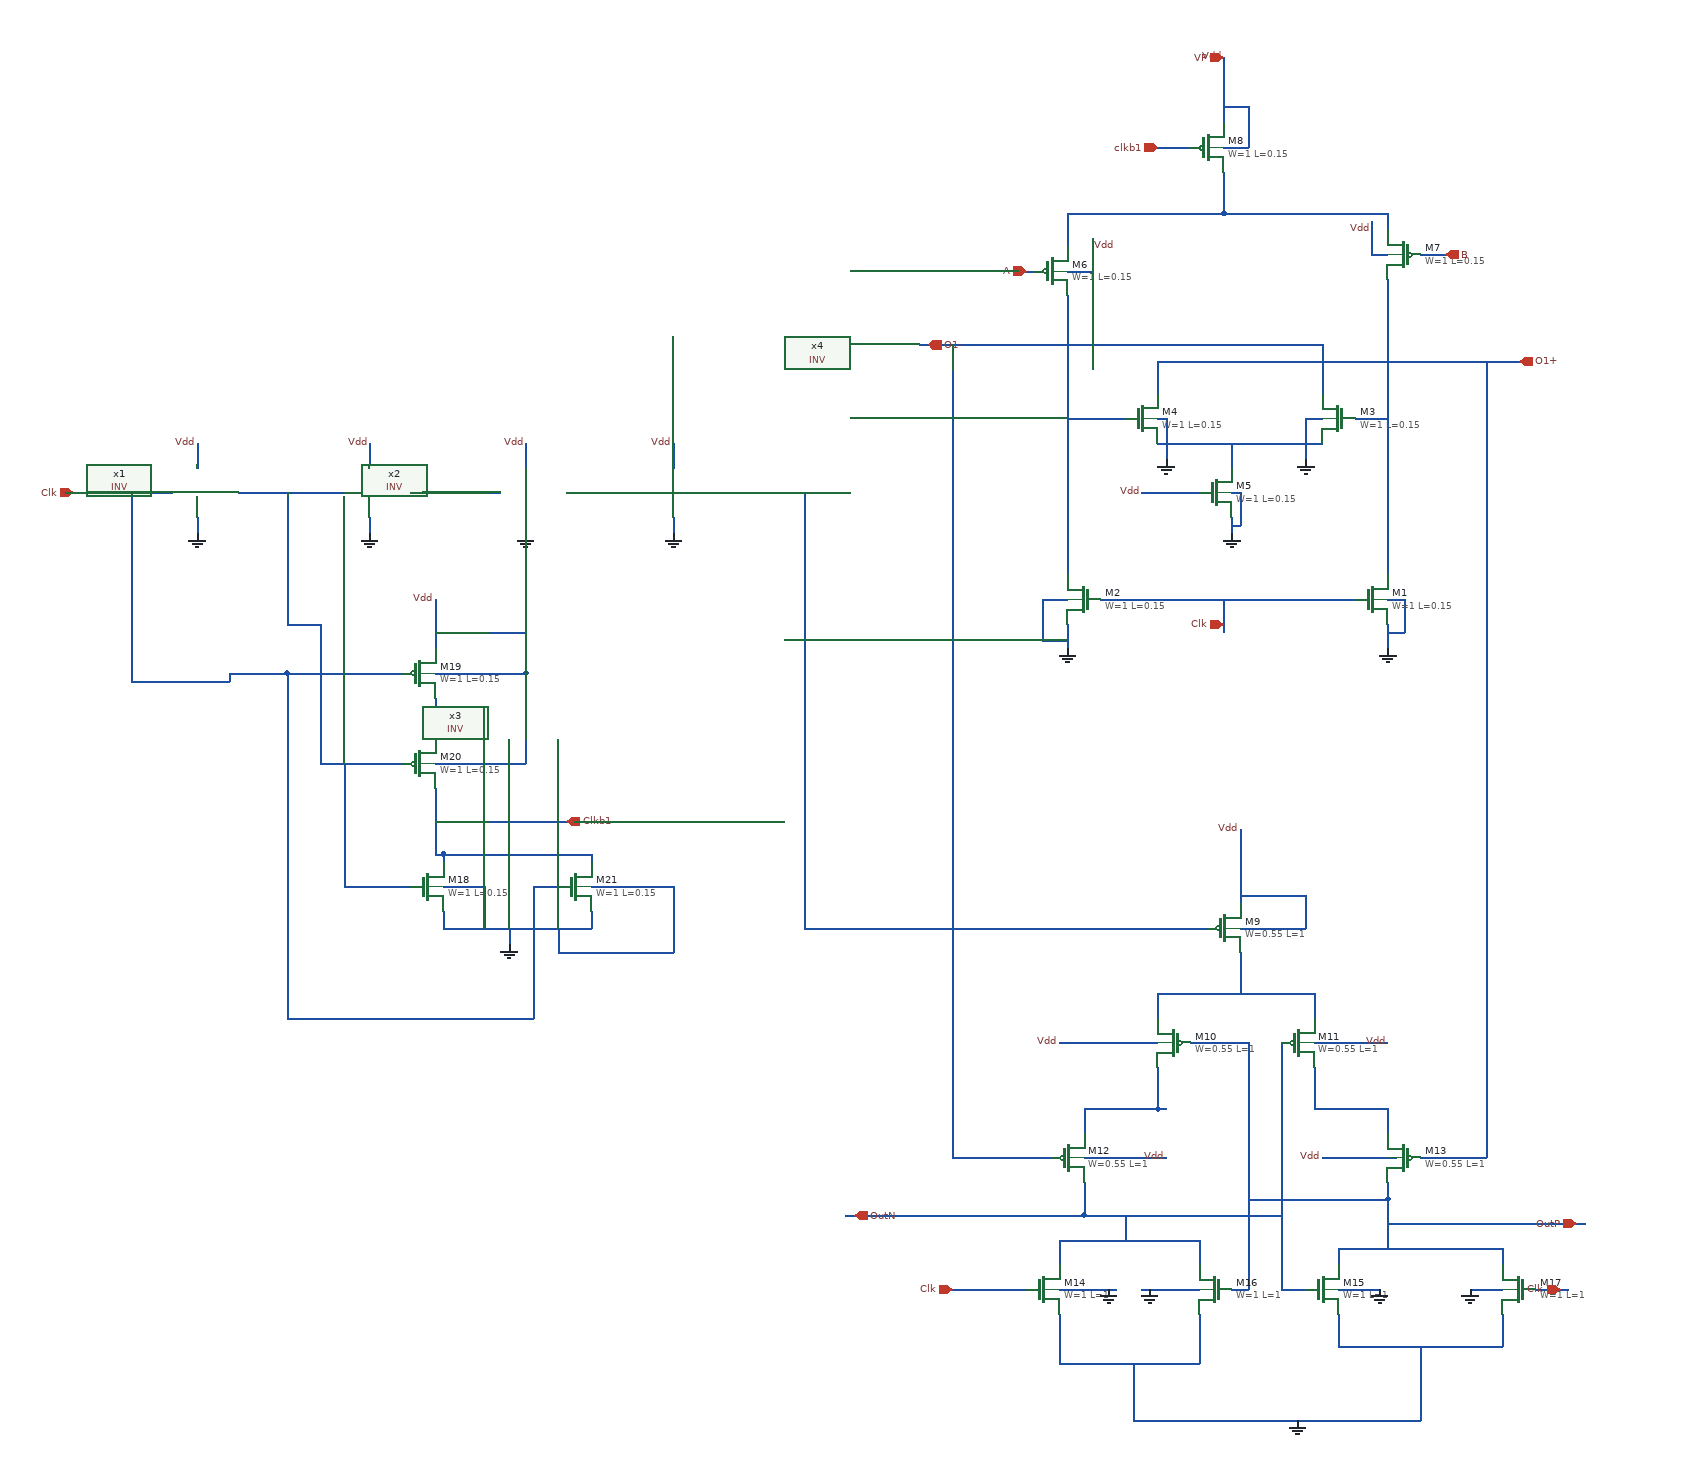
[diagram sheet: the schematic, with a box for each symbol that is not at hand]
v {xschem version=3.0.0 file_version=1.2 }
G {}
K {}
V {}
S {}
E {}
N 1630 -1690 1630 -1640 {
lab=#net1}
N 1630 -1640 1830 -1640 {
lab=#net1}
N 1830 -1640 1830 -1620 {
lab=#net1}
N 1440 -1640 1630 -1640 {
lab=#net1}
N 1440 -1640 1440 -1600 {
lab=#net1}
N 1830 -1560 1830 -1200 {
lab=O1+}
N 1440 -1540 1440 -1200 {
lab=O1-}
N 1480 -1170 1790 -1170 {
lab=Clk}
N 1550 -1360 1750 -1360 {
lab=#net2}
N 1640 -1360 1640 -1330 {
lab=#net2}
N 1530 -1300 1600 -1300 {
lab=Vdd}
N 1550 -1460 1550 -1420 {
lab=O1+}
N 1550 -1460 1830 -1460 {
lab=O1+}
N 1750 -1480 1750 -1420 {
lab=O1-}
N 1440 -1480 1750 -1480 {
lab=O1-}
N 1440 -1390 1510 -1390 {
lab=O1-}
N 1790 -1390 1830 -1390 {
lab=O1+}
N 1630 -1830 1630 -1750 {
lab=VP}
N 1540 -1720 1590 -1720 {
lab=clkb1}
N 1440 -1140 1440 -1110 {
lab=GND}
N 1830 -1140 1830 -1110 {
lab=GND}
N 1640 -1270 1640 -1250 {
lab=GND}
N 1380 -1570 1400 -1570 {
lab=A}
N 1870 -1590 1910 -1590 {
lab=B}
N 1830 -1460 2000 -1460 {
lab=O1+}
N 1260 -1480 1440 -1480 {
lab=O1-}
N 1630 -1170 1630 -1130 {
lab=Clk}
N 1630 -1770 1660 -1770 {
lab=Vdd}
N 1660 -1770 1660 -1720 {
lab=Vdd}
N 1630 -1720 1660 -1720 {
lab=Vdd}
N 1470 -1610 1470 -1570 {
lab=Vdd}
N 1440 -1570 1470 -1570 {
lab=Vdd}
N 1810 -1630 1810 -1590 {
lab=Vdd}
N 1810 -1590 1830 -1590 {
lab=Vdd}
N 1550 -1390 1560 -1390 {
lab=GND}
N 1730 -1390 1750 -1390 {
lab=GND}
N 1640 -1260 1650 -1260 {
lab=GND}
N 1650 -1300 1650 -1260 {
lab=GND}
N 1640 -1300 1650 -1300 {
lab=GND}
N 1410 -1170 1440 -1170 {
lab=GND}
N 1410 -1170 1410 -1120 {
lab=GND}
N 1410 -1120 1440 -1120 {
lab=GND}
N 1830 -1170 1850 -1170 {
lab=GND}
N 1850 -1170 1850 -1130 {
lab=GND}
N 1830 -1130 1850 -1130 {
lab=GND}
N 1560 -1390 1560 -1340 {
lab=GND}
N 1730 -1390 1730 -1340 {
lab=GND}
N 430 -1300 560 -1300 {
lab=#net3}
N 640 -1300 750 -1300 {
lab=#net4}
N 830 -1300 930 -1300 {
lab=#net5}
N 380 -1360 380 -1330 {
lab=Vdd}
N 590 -1360 590 -1330 {
lab=Vdd}
N 780 -1360 780 -1330 {
lab=Vdd}
N 960 -1360 960 -1330 {
lab=Vdd}
N 220 -1300 350 -1300 {
lab=Clk}
N 300 -1300 300 -1100 {
lab=Clk}
N 490 -1300 490 -1140 {
lab=#net3}
N 380 -1270 380 -1250 {
lab=GND}
N 590 -1270 590 -1250 {
lab=GND}
N 780 -1270 780 -1250 {
lab=GND}
N 960 -1270 960 -1250 {
lab=GND}
N 1650 -740 1650 -690 {
lab=#net6}
N 1550 -690 1550 -660 {
lab=#net6}
N 1740 -690 1740 -660 {
lab=#net6}
N 1550 -600 1550 -590 {
lab=#net7}
N 1550 -600 1550 -550 {
lab=#net7}
N 1460 -550 1550 -550 {
lab=#net7}
N 1460 -550 1460 -520 {
lab=#net7}
N 1830 -550 1830 -520 {
lab=#net8}
N 1740 -550 1830 -550 {
lab=#net8}
N 1740 -600 1740 -550 {
lab=#net8}
N 1700 -630 1700 -330 {
lab=OutN}
N 1700 -330 1730 -330 {
lab=OutN}
N 1640 -330 1660 -330 {
lab=OutP}
N 1660 -630 1660 -330 {
lab=OutP}
N 1590 -630 1660 -630 {
lab=OutP}
N 1830 -460 1830 -440 {
lab=OutP}
N 1660 -440 1830 -440 {
lab=OutP}
N 1460 -460 1460 -420 {
lab=OutN}
N 1460 -420 1700 -420 {
lab=OutN}
N 1600 -390 1600 -360 {
lab=OutN}
N 1430 -390 1600 -390 {
lab=OutN}
N 1430 -390 1430 -360 {
lab=OutN}
N 1970 -380 1970 -360 {
lab=OutP}
N 1770 -380 1970 -380 {
lab=OutP}
N 1770 -380 1770 -360 {
lab=OutP}
N 1970 -300 1970 -260 {
lab=GND}
N 1770 -260 1970 -260 {
lab=GND}
N 1770 -300 1770 -260 {
lab=GND}
N 1600 -300 1600 -240 {
lab=GND}
N 1430 -300 1430 -240 {
lab=GND}
N 1530 -330 1600 -330 {
lab=GND}
N 1430 -330 1500 -330 {
lab=GND}
N 1870 -260 1870 -170 {
lab=GND}
N 1520 -170 1870 -170 {
lab=GND}
N 1520 -240 1520 -170 {
lab=GND}
N 1870 -490 1950 -490 {
lab=O1+}
N 1380 -490 1420 -490 {
lab=O1-}
N 2010 -330 2050 -330 {
lab=Clk}
N 1290 -330 1390 -330 {
lab=Clk}
N 1740 -630 1830 -630 {
lab=Vdd}
N 1430 -630 1550 -630 {
lab=Vdd}
N 1830 -440 1830 -380 {
lab=OutP}
N 1510 -420 1510 -390 {
lab=OutN}
N 1460 -490 1560 -490 {
lab=Vdd}
N 1550 -550 1560 -550 {
lab=#net7}
N 1750 -490 1840 -490 {
lab=Vdd}
N 1770 -330 1820 -330 {
lab=GND}
N 1930 -330 1970 -330 {
lab=GND}
N 1650 -770 1730 -770 {
lab=Vdd}
N 1730 -810 1730 -770 {
lab=Vdd}
N 1710 -810 1730 -810 {
lab=Vdd}
N 1650 -810 1710 -810 {
lab=Vdd}
N 1650 -810 1650 -800 {
lab=Vdd}
N 1650 -890 1650 -800 {
lab=Vdd}
N 1170 -420 1460 -420 {
lab=OutN}
N 1830 -410 2070 -410 {
lab=OutP}
N 1550 -690 1740 -690 {
lab=#net6}
N 1300 -1480 1300 -490 {
lab=O1-}
N 1300 -490 1380 -490 {
lab=O1-}
N 1950 -1460 1950 -720 {
lab=O1+}
N 1950 -720 1950 -490 {
lab=O1+}
N 1430 -240 1600 -240 {
lab=GND}
N 670 -940 670 -860 {
lab=Clkb1}
N 670 -860 680 -860 {
lab=Clkb1}
N 680 -860 680 -850 {
lab=Clkb1}
N 680 -860 860 -860 {
lab=Clkb1}
N 860 -860 860 -850 {
lab=Clkb1}
N 670 -1050 670 -1000 {
lab=#net9}
N 670 -1170 670 -1110 {
lab=Vdd}
N 680 -790 680 -770 {
lab=GND}
N 680 -770 860 -770 {
lab=GND}
N 860 -790 860 -770 {
lab=GND}
N 760 -770 760 -750 {
lab=GND}
N 540 -1080 630 -1080 {
lab=Clk}
N 540 -970 630 -970 {
lab=#net3}
N 560 -820 640 -820 {
lab=#net3}
N 560 -970 560 -820 {
lab=#net3}
N 790 -820 820 -820 {
lab=Clk}
N 790 -820 790 -740 {
lab=Clk}
N 790 -740 790 -660 {
lab=Clk}
N 490 -660 790 -660 {
lab=Clk}
N 490 -1070 490 -660 {
lab=Clk}
N 490 -1080 490 -1070 {
lab=Clk}
N 490 -1080 540 -1080 {
lab=Clk}
N 420 -1080 490 -1080 {
lab=Clk}
N 670 -900 840 -900 {
lab=Clkb1}
N 670 -1080 780 -1080 {
lab=Vdd}
N 670 -970 780 -970 {
lab=Vdd}
N 680 -820 730 -820 {
lab=GND}
N 860 -820 960 -820 {
lab=GND}
N 730 -820 730 -770 {
lab=GND}
N 960 -820 960 -740 {
lab=GND}
N 820 -740 960 -740 {
lab=GND}
N 820 -770 820 -740 {
lab=GND}
N 780 -1080 780 -970 {
lab=Vdd}
N 780 -1130 780 -1080 {
lab=Vdd}
N 670 -1130 780 -1130 {
lab=Vdd}
N 490 -1140 530 -1140 {
lab=#net3}
N 530 -1140 530 -970 {
lab=#net3}
N 530 -970 540 -970 {
lab=#net3}
N 300 -1100 300 -1070 {
lab=Clk}
N 300 -1070 420 -1070 {
lab=Clk}
N 420 -1080 420 -1070 {
lab=Clk}
N 1120 -770 1610 -770 {
lab=#net10}
N 1120 -1300 1120 -770 {
lab=#net10}
N 1010 -1300 1120 -1300 {
lab=#net10}
C {sky130_fd_pr/nfet_01v8.sym} 1810 -1170 0 0 {name=M1
L=0.15
W=1
nf=1 
mult=1
ad="'int((nf+1)/2) * W/nf * 0.29'" 
pd="'2*int((nf+1)/2) * (W/nf + 0.29)'"
as="'int((nf+2)/2) * W/nf * 0.29'" 
ps="'2*int((nf+2)/2) * (W/nf + 0.29)'"
nrd="'0.29 / W'" nrs="'0.29 / W'"
sa=0 sb=0 sd=0
model=nfet_01v8
spiceprefix=X
}
C {sky130_fd_pr/nfet_01v8.sym} 1460 -1170 0 1 {name=M2
L=0.15
W=1
nf=1 
mult=1
ad="'int((nf+1)/2) * W/nf * 0.29'" 
pd="'2*int((nf+1)/2) * (W/nf + 0.29)'"
as="'int((nf+2)/2) * W/nf * 0.29'" 
ps="'2*int((nf+2)/2) * (W/nf + 0.29)'"
nrd="'0.29 / W'" nrs="'0.29 / W'"
sa=0 sb=0 sd=0
model=nfet_01v8
spiceprefix=X
}
C {sky130_fd_pr/nfet_01v8.sym} 1770 -1390 0 1 {name=M3
L=0.15
W=1
nf=1 
mult=1
ad="'int((nf+1)/2) * W/nf * 0.29'" 
pd="'2*int((nf+1)/2) * (W/nf + 0.29)'"
as="'int((nf+2)/2) * W/nf * 0.29'" 
ps="'2*int((nf+2)/2) * (W/nf + 0.29)'"
nrd="'0.29 / W'" nrs="'0.29 / W'"
sa=0 sb=0 sd=0
model=nfet_01v8
spiceprefix=X
}
C {sky130_fd_pr/nfet_01v8.sym} 1530 -1390 0 0 {name=M4
L=0.15
W=1
nf=1 
mult=1
ad="'int((nf+1)/2) * W/nf * 0.29'" 
pd="'2*int((nf+1)/2) * (W/nf + 0.29)'"
as="'int((nf+2)/2) * W/nf * 0.29'" 
ps="'2*int((nf+2)/2) * (W/nf + 0.29)'"
nrd="'0.29 / W'" nrs="'0.29 / W'"
sa=0 sb=0 sd=0
model=nfet_01v8
spiceprefix=X
}
C {sky130_fd_pr/nfet_01v8.sym} 1620 -1300 0 0 {name=M5
L=0.15
W=1
nf=1 
mult=1
ad="'int((nf+1)/2) * W/nf * 0.29'" 
pd="'2*int((nf+1)/2) * (W/nf + 0.29)'"
as="'int((nf+2)/2) * W/nf * 0.29'" 
ps="'2*int((nf+2)/2) * (W/nf + 0.29)'"
nrd="'0.29 / W'" nrs="'0.29 / W'"
sa=0 sb=0 sd=0
model=nfet_01v8
spiceprefix=X
}
C {sky130_fd_pr/pfet_01v8.sym} 1420 -1570 0 0 {name=M6
L=0.15
W=1
nf=1
mult=1
ad="'int((nf+1)/2) * W/nf * 0.29'" 
pd="'2*int((nf+1)/2) * (W/nf + 0.29)'"
as="'int((nf+2)/2) * W/nf * 0.29'" 
ps="'2*int((nf+2)/2) * (W/nf + 0.29)'"
nrd="'0.29 / W'" nrs="'0.29 / W'"
sa=0 sb=0 sd=0
model=pfet_01v8
spiceprefix=X
}
C {sky130_fd_pr/pfet_01v8.sym} 1850 -1590 0 1 {name=M7
L=0.15
W=1
nf=1
mult=1
ad="'int((nf+1)/2) * W/nf * 0.29'" 
pd="'2*int((nf+1)/2) * (W/nf + 0.29)'"
as="'int((nf+2)/2) * W/nf * 0.29'" 
ps="'2*int((nf+2)/2) * (W/nf + 0.29)'"
nrd="'0.29 / W'" nrs="'0.29 / W'"
sa=0 sb=0 sd=0
model=pfet_01v8
spiceprefix=X
}
C {sky130_fd_pr/pfet_01v8.sym} 1610 -1720 0 0 {name=M8
L=0.15
W=1
nf=1
mult=1
ad="'int((nf+1)/2) * W/nf * 0.29'" 
pd="'2*int((nf+1)/2) * (W/nf + 0.29)'"
as="'int((nf+2)/2) * W/nf * 0.29'" 
ps="'2*int((nf+2)/2) * (W/nf + 0.29)'"
nrd="'0.29 / W'" nrs="'0.29 / W'"
sa=0 sb=0 sd=0
model=pfet_01v8
spiceprefix=X
}
C {devices/gnd.sym} 1440 -1110 0 0 {name=l1 lab=GND}
C {devices/gnd.sym} 1830 -1110 0 0 {name=l2 lab=GND}
C {devices/gnd.sym} 1640 -1250 0 0 {name=l3 lab=GND}
C {devices/ipin.sym} 1550 -1720 0 0 {name=p1 lab=clkb1}
C {devices/ipin.sym} 1390 -1570 0 0 {name=p2 lab=A}
C {devices/ipin.sym} 1900 -1590 0 1 {name=p3 lab=B}
C {devices/opin.sym} 1990 -1460 0 0 {name=p6 lab=O1+}
C {devices/opin.sym} 1270 -1480 2 0 {name=p7 lab=O1-}
C {devices/lab_pin.sym} 1630 -1830 0 0 {name=l4 sig_type=std_logic lab=Vdd}
C {devices/lab_pin.sym} 1530 -1300 0 0 {name=l5 sig_type=std_logic lab=Vdd}
C {devices/ipin.sym} 1630 -1140 3 0 {name=p4 lab=Clk}
C {devices/gnd.sym} 1560 -1340 0 0 {name=l16 lab=GND}
C {devices/gnd.sym} 1730 -1340 0 0 {name=l17 lab=GND}
C {devices/lab_pin.sym} 1810 -1620 0 0 {name=l18 sig_type=std_logic lab=Vdd}
C {devices/lab_pin.sym} 1470 -1600 2 0 {name=l19 sig_type=std_logic lab=Vdd}
C {devices/lab_pin.sym} 380 -1360 1 0 {name=l20 sig_type=std_logic lab=Vdd}
C {devices/lab_pin.sym} 590 -1360 1 0 {name=l21 sig_type=std_logic lab=Vdd}
C {devices/lab_pin.sym} 780 -1360 1 0 {name=l31 sig_type=std_logic lab=Vdd}
C {devices/lab_pin.sym} 960 -1360 1 0 {name=l34 sig_type=std_logic lab=Vdd}
C {devices/gnd.sym} 380 -1250 0 0 {name=l36 lab=GND}
C {devices/gnd.sym} 590 -1250 0 0 {name=l37 lab=GND}
C {devices/gnd.sym} 780 -1250 0 0 {name=l38 lab=GND}
C {devices/gnd.sym} 960 -1250 0 0 {name=l39 lab=GND}
C {devices/ipin.sym} 230 -1300 0 0 {name=p12 lab=Clk}
C {sky130_fd_pr/pfet_01v8.sym} 1630 -770 0 0 {name=M9
L=1
W=0.55
ad="'W * 0.29'" pd="'W + 2 * 0.29'"
as="'W * 0.29'" ps="'W + 2 * 0.29'"
nrd=0 nrs=0
sa=0 sb=0 sd=0
nf=1 mult=1
model=pfet_01v8
spiceprefix=X
 }
C {sky130_fd_pr/pfet_01v8.sym} 1570 -630 0 1 {name=M10
L=1
W=0.55
ad="'W * 0.29'" pd="'W + 2 * 0.29'"
as="'W * 0.29'" ps="'W + 2 * 0.29'"
nrd=0 nrs=0
sa=0 sb=0 sd=0
nf=1 mult=1
model=pfet_01v8
spiceprefix=X
 }
C {sky130_fd_pr/pfet_01v8.sym} 1720 -630 0 0 {name=M11
L=1
W=0.55
ad="'W * 0.29'" pd="'W + 2 * 0.29'"
as="'W * 0.29'" ps="'W + 2 * 0.29'"
nrd=0 nrs=0
sa=0 sb=0 sd=0
nf=1 mult=1
model=pfet_01v8
spiceprefix=X
 }
C {sky130_fd_pr/pfet_01v8.sym} 1440 -490 0 0 {name=M12
L=1
W=0.55
ad="'W * 0.29'" pd="'W + 2 * 0.29'"
as="'W * 0.29'" ps="'W + 2 * 0.29'"
nrd=0 nrs=0
sa=0 sb=0 sd=0
nf=1 mult=1
model=pfet_01v8
spiceprefix=X
 }
C {sky130_fd_pr/pfet_01v8.sym} 1850 -490 0 1 {name=M13
L=1
W=0.55
ad="'W * 0.29'" pd="'W + 2 * 0.29'"
as="'W * 0.29'" ps="'W + 2 * 0.29'"
nrd=0 nrs=0
sa=0 sb=0 sd=0
nf=1 mult=1
model=pfet_01v8
spiceprefix=X
 }
C {sky130_fd_pr/nfet_01v8_lvt.sym} 1410 -330 0 0 {name=M14
L=1
W=1
ad="'W * 0.29'" pd="'2*(W + 0.29)'"
as="'W * 0.29'" ps="'2*(W + 0.29)'"
nrd=0 nrs=0
sa=0 sb=0 sd=0
nf=1 mult=1
model=nfet_01v8_lvt
spiceprefix=X
 }
C {sky130_fd_pr/nfet_01v8_lvt.sym} 1750 -330 0 0 {name=M15
L=1
W=1
ad="'W * 0.29'" pd="'2*(W + 0.29)'"
as="'W * 0.29'" ps="'2*(W + 0.29)'"
nrd=0 nrs=0
sa=0 sb=0 sd=0
nf=1 mult=1
model=nfet_01v8_lvt
spiceprefix=X
 }
C {sky130_fd_pr/nfet_01v8_lvt.sym} 1620 -330 0 1 {name=M16
L=1
W=1
ad="'W * 0.29'" pd="'2*(W + 0.29)'"
as="'W * 0.29'" ps="'2*(W + 0.29)'"
nrd=0 nrs=0
sa=0 sb=0 sd=0
nf=1 mult=1
model=nfet_01v8_lvt
spiceprefix=X
 }
C {sky130_fd_pr/nfet_01v8_lvt.sym} 1990 -330 0 1 {name=M17
L=1
W=1
ad="'W * 0.29'" pd="'2*(W + 0.29)'"
as="'W * 0.29'" ps="'2*(W + 0.29)'"
nrd=0 nrs=0
sa=0 sb=0 sd=0
nf=1 mult=1
model=nfet_01v8_lvt
spiceprefix=X
 }
C {devices/lab_pin.sym} 1650 -890 0 0 {name=l22 sig_type=std_logic lab=Vdd
}
C {devices/gnd.sym} 1720 -170 0 0 {name=l23 lab=GND}
C {devices/opin.sym} 2060 -410 2 1 {name=p9 lab=OutP}
C {devices/opin.sym} 1180 -420 2 0 {name=p10 lab=OutN}
C {devices/lab_pin.sym} 1430 -630 1 0 {name=l24 sig_type=std_logic lab=Vdd
}
C {devices/lab_pin.sym} 1830 -630 1 0 {name=l25 sig_type=std_logic lab=Vdd
}
C {devices/lab_pin.sym} 1560 -490 1 0 {name=l26 sig_type=std_logic lab=Vdd
}
C {devices/lab_pin.sym} 1750 -490 1 0 {name=l27 sig_type=std_logic lab=Vdd
}
C {devices/gnd.sym} 1490 -330 0 0 {name=l28 lab=GND}
C {devices/gnd.sym} 1540 -330 0 0 {name=l29 lab=GND}
C {devices/gnd.sym} 1820 -330 0 0 {name=l30 lab=GND}
C {devices/gnd.sym} 1930 -330 0 0 {name=l32 lab=GND}
C {devices/ipin.sym} 1300 -330 0 0 {name=p5 lab=Clk}
C {devices/ipin.sym} 2040 -330 2 0 {name=p11 lab=Clk}
C {sky130_fd_pr/nfet_01v8.sym} 660 -820 0 0 {name=M18
L=0.15
W=1
nf=1 
mult=1
ad="'int((nf+1)/2) * W/nf * 0.29'" 
pd="'2*int((nf+1)/2) * (W/nf + 0.29)'"
as="'int((nf+2)/2) * W/nf * 0.29'" 
ps="'2*int((nf+2)/2) * (W/nf + 0.29)'"
nrd="'0.29 / W'" nrs="'0.29 / W'"
sa=0 sb=0 sd=0
model=nfet_01v8
spiceprefix=X
}
C {sky130_fd_pr/pfet_01v8.sym} 650 -1080 0 0 {name=M19
L=0.15
W=1
nf=1
mult=1
ad="'int((nf+1)/2) * W/nf * 0.29'" 
pd="'2*int((nf+1)/2) * (W/nf + 0.29)'"
as="'int((nf+2)/2) * W/nf * 0.29'" 
ps="'2*int((nf+2)/2) * (W/nf + 0.29)'"
nrd="'0.29 / W'" nrs="'0.29 / W'"
sa=0 sb=0 sd=0
model=pfet_01v8
spiceprefix=X
}
C {sky130_fd_pr/pfet_01v8.sym} 650 -970 0 0 {name=M20
L=0.15
W=1
nf=1
mult=1
ad="'int((nf+1)/2) * W/nf * 0.29'" 
pd="'2*int((nf+1)/2) * (W/nf + 0.29)'"
as="'int((nf+2)/2) * W/nf * 0.29'" 
ps="'2*int((nf+2)/2) * (W/nf + 0.29)'"
nrd="'0.29 / W'" nrs="'0.29 / W'"
sa=0 sb=0 sd=0
model=pfet_01v8
spiceprefix=X
}
C {sky130_fd_pr/nfet_01v8.sym} 840 -820 0 0 {name=M21
L=0.15
W=1
nf=1 
mult=1
ad="'int((nf+1)/2) * W/nf * 0.29'" 
pd="'2*int((nf+1)/2) * (W/nf + 0.29)'"
as="'int((nf+2)/2) * W/nf * 0.29'" 
ps="'2*int((nf+2)/2) * (W/nf + 0.29)'"
nrd="'0.29 / W'" nrs="'0.29 / W'"
sa=0 sb=0 sd=0
model=nfet_01v8
spiceprefix=X
}
C {devices/opin.sym} 830 -900 0 0 {name=p16 lab=Clkb1}
C {devices/lab_pin.sym} 670 -1170 0 0 {name=l33 sig_type=std_logic lab=Vdd}
C {devices/gnd.sym} 760 -750 0 0 {name=l35 lab=GND}
C {pico/main_comparator/inverter/INV.sym} 330 -1300 0 0 {name=x1}
C {pico/main_comparator/inverter/INV.sym} 540 -1300 0 0 {name=x2}
C {pico/main_comparator/inverter/INV.sym} 730 -1300 0 0 {name=x3}
C {pico/main_comparator/inverter/INV.sym} 910 -1300 0 0 {name=x4}
C {devices/iopin.sym} 1630 -1830 0 0 {name=p14 lab=VP}
